VERSION 5.8 ;
BUSBITCHARS "[]" ;
DIVIDERCHAR "/" ;
USEMINSPACING OBS OFF ;
CLEARANCEMEASURE EUCLIDEAN ;

UNITS
  DATABASE MICRONS 2000 ;
END UNITS

MANUFACTURINGGRID 0.0005 ;

PROPERTYDEFINITIONS
  LAYER LEF58_RIGHTWAYONGRIDONLY STRING ;
  LAYER LEF58_RECTONLY STRING ;
END PROPERTYDEFINITIONS

SITE coresite
    SIZE 0.045 BY 0.1440 ;
    CLASS CORE ;
    SYMMETRY Y ;
END coresite
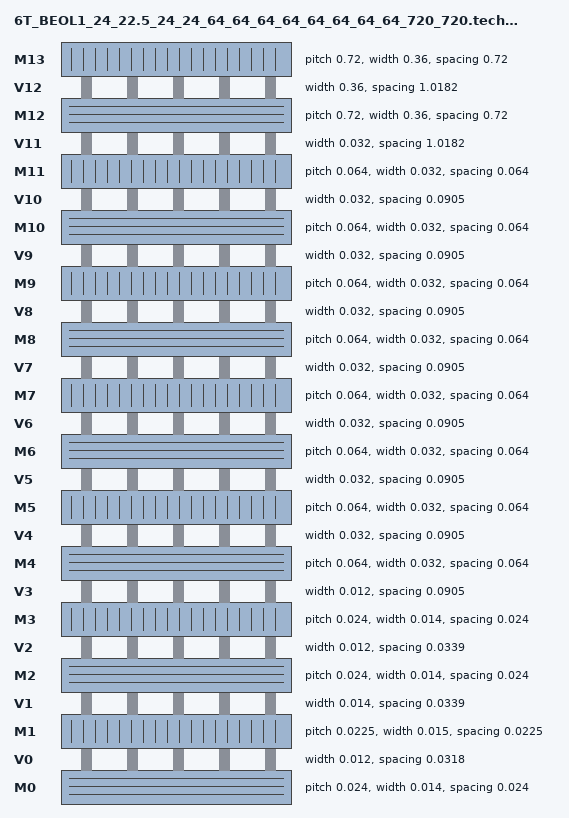
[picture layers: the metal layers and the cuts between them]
LAYER M0
  TYPE ROUTING ;
  DIRECTION HORIZONTAL ;
  PITCH 0.0240 ;
  OFFSET 0.0 ;
  WIDTH 0.0140 ;
  MINWIDTH 0.0140 ;
  AREA 0.0003 ;
  SPACING 0.0240 ENDOFLINE 0.0240 WITHIN 0.001 ;
  SPACING 0.0100 ;
  SPACINGTABLE  PARALLELRUNLENGTH
                0  
  WIDTH 0       0.0100 ; 
  PROPERTY LEF58_RIGHTWAYONGRIDONLY " RIGHTWAYONGRIDONLY ; " ;
  PROPERTY LEF58_RECTONLY " RECTONLY ; " ;
END M0
LAYER V0
  TYPE CUT ;
  WIDTH 0.0120 ;
  SPACING 0.0318 CENTERTOCENTER ;
END V0
LAYER M1
  TYPE ROUTING ;
  DIRECTION VERTICAL ;
  PITCH 0.0225 ;
  OFFSET 0.0 ;
  WIDTH 0.0150 ;
  MINWIDTH 0.0150 ;
  AREA 0.0003 ;
  SPACING 0.0225 ENDOFLINE 0.0225 WITHIN 0.001 ;
  SPACING 0.0075 ;
  SPACINGTABLE  PARALLELRUNLENGTH
                0  
  WIDTH 0       0.0075 ; 
  PROPERTY LEF58_RIGHTWAYONGRIDONLY " RIGHTWAYONGRIDONLY ; " ;
  PROPERTY LEF58_RECTONLY " RECTONLY ; " ;
END M1
LAYER V1
  TYPE CUT ;
  WIDTH 0.0140 ;
  SPACING 0.0339 CENTERTOCENTER ;
END V1
LAYER M2
  TYPE ROUTING ;
  DIRECTION HORIZONTAL ;
  PITCH 0.0240 ;
  OFFSET 0.0 ;
  WIDTH 0.0140 ;
  MINWIDTH 0.0140 ;
  AREA 0.0003 ;
  SPACING 0.0240 ENDOFLINE 0.0240 WITHIN 0.001 ;
  SPACING 0.0100 ;
  SPACINGTABLE  PARALLELRUNLENGTH
                0  
  WIDTH 0       0.0100 ; 
  PROPERTY LEF58_RIGHTWAYONGRIDONLY " RIGHTWAYONGRIDONLY ; " ;
  PROPERTY LEF58_RECTONLY " RECTONLY ; " ;
END M2
LAYER V2
  TYPE CUT ;
  WIDTH 0.0120 ;
  SPACING 0.0339 CENTERTOCENTER ;
END V2
LAYER M3
  TYPE ROUTING ;
  DIRECTION VERTICAL ;
  PITCH 0.0240 ;
  OFFSET 0.0 ;
  WIDTH 0.0140 ;
  MINWIDTH 0.0140 ;
  AREA 0.0003 ;
  SPACING 0.0240 ENDOFLINE 0.0240 WITHIN 0.001 ;
  SPACING 0.0100 ;
  SPACINGTABLE  PARALLELRUNLENGTH
                0  
  WIDTH 0       0.0100 ; 
  PROPERTY LEF58_RIGHTWAYONGRIDONLY " RIGHTWAYONGRIDONLY ; " ;
  PROPERTY LEF58_RECTONLY " RECTONLY ; " ;
END M3
LAYER V3
  TYPE CUT ;
  WIDTH 0.0120 ;
  SPACING 0.0905 CENTERTOCENTER ;
END V3
LAYER M4
  TYPE ROUTING ;
  DIRECTION HORIZONTAL ;
  PITCH 0.0640 ;
  OFFSET 0.0 ;
  WIDTH 0.0320 ;
  MINWIDTH 0.0320 ;
  AREA 0.0020 ;
  SPACING 0.0640 ENDOFLINE 0.0640 WITHIN 0.001 ;
  SPACING 0.0320 ;
  SPACINGTABLE  PARALLELRUNLENGTH
                0  
  WIDTH 0       0.0320 ; 
  PROPERTY LEF58_RIGHTWAYONGRIDONLY " RIGHTWAYONGRIDONLY ; " ;
  PROPERTY LEF58_RECTONLY " RECTONLY ; " ;
END M4
LAYER V4
  TYPE CUT ;
  WIDTH 0.0320 ;
  SPACING 0.0905 CENTERTOCENTER ;
END V4
LAYER M5
  TYPE ROUTING ;
  DIRECTION VERTICAL ;
  PITCH 0.0640 ;
  OFFSET 0.0 ;
  WIDTH 0.0320 ;
  MINWIDTH 0.0320 ;
  AREA 0.0020 ;
  SPACING 0.0640 ENDOFLINE 0.0640 WITHIN 0.001 ;
  SPACING 0.0320 ;
  SPACINGTABLE  PARALLELRUNLENGTH
                0  
  WIDTH 0       0.0320 ; 
  PROPERTY LEF58_RIGHTWAYONGRIDONLY " RIGHTWAYONGRIDONLY ; " ;
  PROPERTY LEF58_RECTONLY " RECTONLY ; " ;
END M5
LAYER V5
  TYPE CUT ;
  WIDTH 0.0320 ;
  SPACING 0.0905 CENTERTOCENTER ;
END V5
LAYER M6
  TYPE ROUTING ;
  DIRECTION HORIZONTAL ;
  PITCH 0.0640 ;
  OFFSET 0.0 ;
  WIDTH 0.0320 ;
  MINWIDTH 0.0320 ;
  AREA 0.0020 ;
  SPACING 0.0640 ENDOFLINE 0.0640 WITHIN 0.001 ;
  SPACING 0.0320 ;
  SPACINGTABLE  PARALLELRUNLENGTH
                0  
  WIDTH 0       0.0320 ; 
  PROPERTY LEF58_RIGHTWAYONGRIDONLY " RIGHTWAYONGRIDONLY ; " ;
  PROPERTY LEF58_RECTONLY " RECTONLY ; " ;
END M6
LAYER V6
  TYPE CUT ;
  WIDTH 0.0320 ;
  SPACING 0.0905 CENTERTOCENTER ;
END V6
LAYER M7
  TYPE ROUTING ;
  DIRECTION VERTICAL ;
  PITCH 0.0640 ;
  OFFSET 0.0 ;
  WIDTH 0.0320 ;
  MINWIDTH 0.0320 ;
  AREA 0.0020 ;
  SPACING 0.0640 ENDOFLINE 0.0640 WITHIN 0.001 ;
  SPACING 0.0320 ;
  SPACINGTABLE  PARALLELRUNLENGTH
                0  
  WIDTH 0       0.0320 ; 
  PROPERTY LEF58_RIGHTWAYONGRIDONLY " RIGHTWAYONGRIDONLY ; " ;
  PROPERTY LEF58_RECTONLY " RECTONLY ; " ;
END M7
LAYER V7
  TYPE CUT ;
  WIDTH 0.0320 ;
  SPACING 0.0905 CENTERTOCENTER ;
END V7
LAYER M8
  TYPE ROUTING ;
  DIRECTION HORIZONTAL ;
  PITCH 0.0640 ;
  OFFSET 0.0 ;
  WIDTH 0.0320 ;
  MINWIDTH 0.0320 ;
  AREA 0.0020 ;
  SPACING 0.0640 ENDOFLINE 0.0640 WITHIN 0.001 ;
  SPACING 0.0320 ;
  SPACINGTABLE  PARALLELRUNLENGTH
                0  
  WIDTH 0       0.0320 ; 
  PROPERTY LEF58_RIGHTWAYONGRIDONLY " RIGHTWAYONGRIDONLY ; " ;
  PROPERTY LEF58_RECTONLY " RECTONLY ; " ;
END M8
LAYER V8
  TYPE CUT ;
  WIDTH 0.0320 ;
  SPACING 0.0905 CENTERTOCENTER ;
END V8
LAYER M9
  TYPE ROUTING ;
  DIRECTION VERTICAL ;
  PITCH 0.0640 ;
  OFFSET 0.0 ;
  WIDTH 0.0320 ;
  MINWIDTH 0.0320 ;
  AREA 0.0020 ;
  SPACING 0.0640 ENDOFLINE 0.0640 WITHIN 0.001 ;
  SPACING 0.0320 ;
  SPACINGTABLE  PARALLELRUNLENGTH
                0  
  WIDTH 0       0.0320 ; 
  PROPERTY LEF58_RIGHTWAYONGRIDONLY " RIGHTWAYONGRIDONLY ; " ;
  PROPERTY LEF58_RECTONLY " RECTONLY ; " ;
END M9
LAYER V9
  TYPE CUT ;
  WIDTH 0.0320 ;
  SPACING 0.0905 CENTERTOCENTER ;
END V9
LAYER M10
  TYPE ROUTING ;
  DIRECTION HORIZONTAL ;
  PITCH 0.0640 ;
  OFFSET 0.0 ;
  WIDTH 0.0320 ;
  MINWIDTH 0.0320 ;
  AREA 0.0020 ;
  SPACING 0.0640 ENDOFLINE 0.0640 WITHIN 0.001 ;
  SPACING 0.0320 ;
  SPACINGTABLE  PARALLELRUNLENGTH
                0  
  WIDTH 0       0.0320 ; 
  PROPERTY LEF58_RIGHTWAYONGRIDONLY " RIGHTWAYONGRIDONLY ; " ;
  PROPERTY LEF58_RECTONLY " RECTONLY ; " ;
END M10
LAYER V10
  TYPE CUT ;
  WIDTH 0.0320 ;
  SPACING 0.0905 CENTERTOCENTER ;
END V10
LAYER M11
  TYPE ROUTING ;
  DIRECTION VERTICAL ;
  PITCH 0.0640 ;
  OFFSET 0.0 ;
  WIDTH 0.0320 ;
  MINWIDTH 0.0320 ;
  AREA 0.0020 ;
  SPACING 0.0640 ENDOFLINE 0.0640 WITHIN 0.001 ;
  SPACING 0.0320 ;
  SPACINGTABLE  PARALLELRUNLENGTH
                0  
  WIDTH 0       0.0320 ; 
  PROPERTY LEF58_RIGHTWAYONGRIDONLY " RIGHTWAYONGRIDONLY ; " ;
  PROPERTY LEF58_RECTONLY " RECTONLY ; " ;
END M11
LAYER V11
  TYPE CUT ;
  WIDTH 0.0320 ;
  SPACING 1.0182 CENTERTOCENTER ;
END V11
LAYER M12
  TYPE ROUTING ;
  DIRECTION HORIZONTAL ;
  PITCH 0.7200 ;
  OFFSET 0.0 ;
  WIDTH 0.3600 ;
  MINWIDTH 0.3600 ;
  AREA 0.2592 ;
  SPACING 0.7200 ENDOFLINE 0.7200 WITHIN 0.001 ;
  SPACING 0.3600 ;
  SPACINGTABLE  PARALLELRUNLENGTH
                0  
  WIDTH 0       0.3600 ; 
  PROPERTY LEF58_RIGHTWAYONGRIDONLY " RIGHTWAYONGRIDONLY ; " ;
  PROPERTY LEF58_RECTONLY " RECTONLY ; " ;
END M12
LAYER V12
  TYPE CUT ;
  WIDTH 0.3600 ;
  SPACING 1.0182 CENTERTOCENTER ;
END V12
LAYER M13
  TYPE ROUTING ;
  DIRECTION VERTICAL ;
  PITCH 0.7200 ;
  OFFSET 0.0 ;
  WIDTH 0.3600 ;
  MINWIDTH 0.3600 ;
  AREA 0.2592 ;
  SPACING 0.7200 ENDOFLINE 0.7200 WITHIN 0.001 ;
  SPACING 0.3600 ;
  SPACINGTABLE  PARALLELRUNLENGTH
                0  
  WIDTH 0       0.3600 ; 
  PROPERTY LEF58_RIGHTWAYONGRIDONLY " RIGHTWAYONGRIDONLY ; " ;
  PROPERTY LEF58_RECTONLY " RECTONLY ; " ;
END M13
LAYER OVERLAP
  TYPE OVERLAP ;
END OVERLAP
VIARULE V0_RULE GENERATE
  LAYER M0 ;
    ENCLOSURE 0.0035 0.0014000000000000002 ;
  LAYER M1 ;
    ENCLOSURE 0.0035 0.000 ;
  LAYER V0 ;
    RECT -0.0056 -0.0056 0.0056 0.0056 ;
    SPACING 0.0318 BY 0.0318 ;
END V0_RULE
VIARULE V1_RULE GENERATE
  LAYER M1 ;
    ENCLOSURE 0.0035 0.000 ;
  LAYER M2 ;
    ENCLOSURE 0.0035 0.0014000000000000002 ;
  LAYER V1 ;
    RECT -0.0056 -0.0056 0.0056 0.0056 ;
    SPACING 0.0339 BY 0.0339 ;
END V1_RULE
VIARULE V2_RULE GENERATE
  LAYER M2 ;
    ENCLOSURE 0.0035 0.000 ;
  LAYER M3 ;
    ENCLOSURE 0.0035 0.000 ;
  LAYER V2 ;
    RECT -0.0070 -0.0070 0.0070 0.0070 ;
    SPACING 0.0339 BY 0.0339 ;
END V2_RULE
VIARULE V3_RULE GENERATE
  LAYER M3 ;
    ENCLOSURE 0.0035 0.000 ;
  LAYER M4 ;
    ENCLOSURE 0.0035 0.009000000000000001 ;
  LAYER V3 ;
    RECT -0.0070 -0.0070 0.0070 0.0070 ;
    SPACING 0.0905 BY 0.0905 ;
END V3_RULE
VIARULE V4_RULE GENERATE
  LAYER M4 ;
    ENCLOSURE 0.0035 0.000 ;
  LAYER M5 ;
    ENCLOSURE 0.0035 0.000 ;
  LAYER V4 ;
    RECT -0.0160 -0.0160 0.0160 0.0160 ;
    SPACING 0.0905 BY 0.0905 ;
END V4_RULE
VIARULE V5_RULE GENERATE
  LAYER M5 ;
    ENCLOSURE 0.0035 0.000 ;
  LAYER M6 ;
    ENCLOSURE 0.0035 0.000 ;
  LAYER V5 ;
    RECT -0.0160 -0.0160 0.0160 0.0160 ;
    SPACING 0.0905 BY 0.0905 ;
END V5_RULE
VIARULE V6_RULE GENERATE
  LAYER M6 ;
    ENCLOSURE 0.0035 0.000 ;
  LAYER M7 ;
    ENCLOSURE 0.0035 0.000 ;
  LAYER V6 ;
    RECT -0.0160 -0.0160 0.0160 0.0160 ;
    SPACING 0.0905 BY 0.0905 ;
END V6_RULE
VIARULE V7_RULE GENERATE
  LAYER M7 ;
    ENCLOSURE 0.0035 0.000 ;
  LAYER M8 ;
    ENCLOSURE 0.0035 0.000 ;
  LAYER V7 ;
    RECT -0.0160 -0.0160 0.0160 0.0160 ;
    SPACING 0.0905 BY 0.0905 ;
END V7_RULE
VIARULE V8_RULE GENERATE
  LAYER M8 ;
    ENCLOSURE 0.0035 0.000 ;
  LAYER M9 ;
    ENCLOSURE 0.0035 0.000 ;
  LAYER V8 ;
    RECT -0.0160 -0.0160 0.0160 0.0160 ;
    SPACING 0.0905 BY 0.0905 ;
END V8_RULE
VIARULE V9_RULE GENERATE
  LAYER M9 ;
    ENCLOSURE 0.0035 0.000 ;
  LAYER M10 ;
    ENCLOSURE 0.0035 0.000 ;
  LAYER V9 ;
    RECT -0.0160 -0.0160 0.0160 0.0160 ;
    SPACING 0.0905 BY 0.0905 ;
END V9_RULE
VIARULE V10_RULE GENERATE
  LAYER M10 ;
    ENCLOSURE 0.0035 0.000 ;
  LAYER M11 ;
    ENCLOSURE 0.0035 0.000 ;
  LAYER V10 ;
    RECT -0.0160 -0.0160 0.0160 0.0160 ;
    SPACING 0.0905 BY 0.0905 ;
END V10_RULE
VIARULE V11_RULE GENERATE
  LAYER M11 ;
    ENCLOSURE 0.0035 0.000 ;
  LAYER M12 ;
    ENCLOSURE 0.0035 0.16399999999999998 ;
  LAYER V11 ;
    RECT -0.0160 -0.0160 0.0160 0.0160 ;
    SPACING 1.0182 BY 1.0182 ;
END V11_RULE
VIARULE V12_RULE GENERATE
  LAYER M12 ;
    ENCLOSURE 0.0035 0.000 ;
  LAYER M13 ;
    ENCLOSURE 0.0035 0.000 ;
  LAYER V12 ;
    RECT -0.1800 -0.1800 0.1800 0.1800 ;
    SPACING 1.0182 BY 1.0182 ;
END V12_RULE
VIA V0_HV DEFAULT
  LAYER M0 ;
  RECT -0.0091 -0.0070 0.0091 0.0070 ;
  LAYER V0 ;
  RECT -0.0056 -0.0056 0.0056 0.0056 ;
  LAYER M1 ;
  RECT -0.0056 -0.0091 0.0056 0.0091 ;
END V0_HV
VIA V1_VH DEFAULT
  LAYER M1 ;
  RECT -0.0056 -0.0091 0.0056 0.0091 ;
  LAYER V1 ;
  RECT -0.0056 -0.0056 0.0056 0.0056 ;
  LAYER M2 ;
  RECT -0.0091 -0.0070 0.0091 0.0070 ;
END V1_VH
VIA V2_HV DEFAULT
  LAYER M2 ;
  RECT -0.0105 -0.0070 0.0105 0.0070 ;
  LAYER V2 ;
  RECT -0.0070 -0.0070 0.0070 0.0070 ;
  LAYER M3 ;
  RECT -0.0070 -0.0105 0.0070 0.0105 ;
END V2_HV
VIA V3_VH DEFAULT
  LAYER M3 ;
  RECT -0.0070 -0.0105 0.0070 0.0105 ;
  LAYER V3 ;
  RECT -0.0070 -0.0070 0.0070 0.0070 ;
  LAYER M4 ;
  RECT -0.0105 -0.0160 0.0105 0.0160 ;
END V3_VH
VIA V4_HV DEFAULT
  LAYER M4 ;
  RECT -0.0195 -0.0160 0.0195 0.0160 ;
  LAYER V4 ;
  RECT -0.0160 -0.0160 0.0160 0.0160 ;
  LAYER M5 ;
  RECT -0.0160 -0.0195 0.0160 0.0195 ;
END V4_HV
VIA V5_VH DEFAULT
  LAYER M5 ;
  RECT -0.0160 -0.0195 0.0160 0.0195 ;
  LAYER V5 ;
  RECT -0.0160 -0.0160 0.0160 0.0160 ;
  LAYER M6 ;
  RECT -0.0195 -0.0160 0.0195 0.0160 ;
END V5_VH
VIA V6_HV DEFAULT
  LAYER M6 ;
  RECT -0.0195 -0.0160 0.0195 0.0160 ;
  LAYER V6 ;
  RECT -0.0160 -0.0160 0.0160 0.0160 ;
  LAYER M7 ;
  RECT -0.0160 -0.0195 0.0160 0.0195 ;
END V6_HV
VIA V7_VH DEFAULT
  LAYER M7 ;
  RECT -0.0160 -0.0195 0.0160 0.0195 ;
  LAYER V7 ;
  RECT -0.0160 -0.0160 0.0160 0.0160 ;
  LAYER M8 ;
  RECT -0.0195 -0.0160 0.0195 0.0160 ;
END V7_VH
VIA V8_HV DEFAULT
  LAYER M8 ;
  RECT -0.0195 -0.0160 0.0195 0.0160 ;
  LAYER V8 ;
  RECT -0.0160 -0.0160 0.0160 0.0160 ;
  LAYER M9 ;
  RECT -0.0160 -0.0195 0.0160 0.0195 ;
END V8_HV
VIA V9_VH DEFAULT
  LAYER M9 ;
  RECT -0.0160 -0.0195 0.0160 0.0195 ;
  LAYER V9 ;
  RECT -0.0160 -0.0160 0.0160 0.0160 ;
  LAYER M10 ;
  RECT -0.0195 -0.0160 0.0195 0.0160 ;
END V9_VH
VIA V10_HV DEFAULT
  LAYER M10 ;
  RECT -0.0195 -0.0160 0.0195 0.0160 ;
  LAYER V10 ;
  RECT -0.0160 -0.0160 0.0160 0.0160 ;
  LAYER M11 ;
  RECT -0.0160 -0.0195 0.0160 0.0195 ;
END V10_HV
VIA V11_VH DEFAULT
  LAYER M11 ;
  RECT -0.0160 -0.0195 0.0160 0.0195 ;
  LAYER V11 ;
  RECT -0.0160 -0.0160 0.0160 0.0160 ;
  LAYER M12 ;
  RECT -0.0195 -0.1800 0.0195 0.1800 ;
END V11_VH
VIA V12_HV DEFAULT
  LAYER M12 ;
  RECT -0.1835 -0.1800 0.1835 0.1800 ;
  LAYER V12 ;
  RECT -0.1800 -0.1800 0.1800 0.1800 ;
  LAYER M13 ;
  RECT -0.1800 -0.1835 0.1800 0.1835 ;
END V12_HV
END LIBRARY
